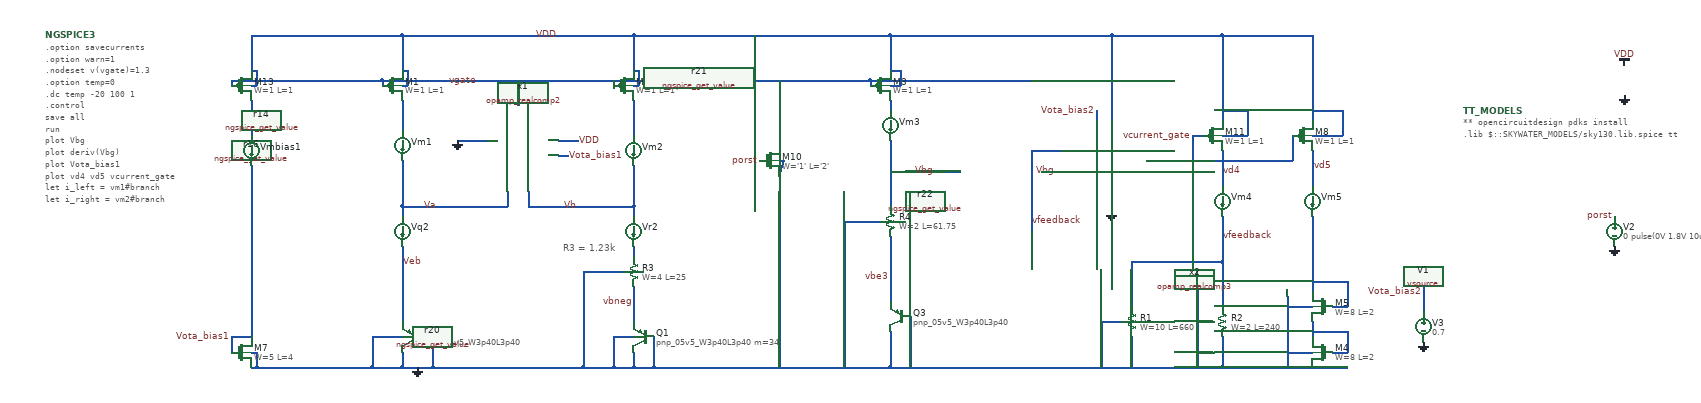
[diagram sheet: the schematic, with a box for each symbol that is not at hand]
v {xschem version=3.0.0 file_version=1.2 }
G {}
K {}
V {}
S {}
E {}
T {R3 = 1.23k} -650 -260 0 0 0.4 0.4 {}
N -970 -40 -970 -10 { lab=GND}
N -1030 -70 -970 -70 { lab=GND}
N -1030 -70 -1030 -10 { lab=GND}
N -970 -670 -750 -670 { lab=VDD}
N -510 -670 -310 -670 { lab=VDD}
N -510 -330 -510 -310 { lab=Vb}
N -510 -410 -510 -330 { lab=Vb}
N 0 -460 0 -330 { lab=Vbg}
N -510 -250 -510 -230 { lab=#net1}
N -510 -540 -510 -470 { lab=#net2}
N -510 -170 -510 -100 { lab=vbneg}
N -470 -70 -470 -10 { lab=GND}
N -510 -40 -510 -10 { lab=GND}
N -550 -70 -510 -70 { lab=GND}
N -550 -70 -550 -10 { lab=GND}
N -930 -70 -910 -70 { lab=GND}
N -910 -70 -910 -10 { lab=GND}
N -610 -200 -530 -200 { lab=GND}
N -610 -200 -610 -10 { lab=GND}
N -970 -250 -970 -100 { lab=Veb}
N -620 -330 -510 -330 { lab=Vb}
N -1270 -40 -1260 -40 { lab=GND}
N -1310 -70 -1310 -40 { lab=Vota_bias1}
N -1310 -70 -1270 -70 { lab=Vota_bias1}
N -1260 -40 -1260 -10 { lab=GND}
N -120 -670 0 -670 { lab=VDD}
N -510 -670 -510 -600 { lab=VDD}
N -120 -10 0 -10 { lab=GND}
N -970 -330 -970 -310 { lab=Va}
N -550 -580 -550 -570 { lab=vgate}
N -1010 -580 -1010 -570 { lab=vgate}
N -970 -540 -970 -480 { lab=#net3}
N -1270 -570 -1260 -570 { lab=VDD}
N -1260 -600 -1260 -570 { lab=VDD}
N -1270 -600 -1260 -600 { lab=VDD}
N -970 -570 -960 -570 { lab=VDD}
N -960 -600 -960 -570 { lab=VDD}
N -970 -600 -960 -600 { lab=VDD}
N -970 -670 -970 -600 { lab=VDD}
N -510 -570 -500 -570 { lab=VDD}
N -500 -600 -500 -570 { lab=VDD}
N -510 -600 -500 -600 { lab=VDD}
N -1230 -670 -970 -670 { lab=VDD}
N -70 -580 -40 -580 { lab=vgate}
N -1310 -580 -1310 -570 { lab=vgate}
N -1270 -670 -1270 -600 { lab=VDD}
N -1270 -350 -1270 -70 { lab=Vota_bias1}
N -970 -330 -900 -330 { lab=Va}
N -1030 -10 -970 -10 { lab=GND}
N -1100 -10 -1030 -10 { lab=GND}
N -1220 -10 -1100 -10 { lab=GND}
N -470 -10 -380 -10 { lab=GND}
N -510 -10 -470 -10 { lab=GND}
N -550 -10 -510 -10 { lab=GND}
N -610 -10 -550 -10 { lab=GND}
N -970 -10 -910 -10 { lab=GND}
N -910 -10 -850 -10 { lab=GND}
N 0 -270 0 -250 { lab=vbe3}
N -310 -670 -120 -670 { lab=VDD}
N -1010 -580 -790 -580 { lab=vgate}
N -790 -580 -310 -580 { lab=vgate}
N -970 -420 -970 -330 { lab=Va}
N -1270 -670 -1230 -670 { lab=VDD}
N -1260 -10 -1220 -10 { lab=GND}
N -1170 -580 -1010 -580 { lab=vgate}
N -1310 -580 -1170 -580 { lab=vgate}
N -270 -670 -270 -650 { lab=VDD}
N -270 -590 -270 -580 { lab=vgate}
N 0 -670 300 -670 {
lab=VDD}
N -720 -330 -620 -330 {
lab=Vb}
N -720 -360 -720 -330 {
lab=Vb}
N -900 -330 -760 -330 {
lab=Va}
N -760 -360 -760 -330 {
lab=Va}
N -740 -580 -740 -530 {
lab=vgate}
N -750 -670 -510 -670 {
lab=VDD}
N -310 -580 -70 -580 {
lab=vgate}
N -850 -10 -610 -10 {
lab=GND}
N -380 -10 -120 -10 {
lab=GND}
N -860 -460 -800 -460 {
lab=GND}
N -660 -460 -620 -460 {
lab=VDD}
N -660 -430 -640 -430 {
lab=Vota_bias1}
N 0 -250 0 -140 {
lab=vbe3}
N 0 -80 0 -10 {
lab=GND}
N 40 -110 40 -10 {
lab=GND}
N 0 -400 140 -400 {
lab=Vbg}
N -1270 -540 -1270 -470 {
lab=#net4}
N -1270 -410 -1270 -350 {
lab=Vota_bias1}
N -90 -300 -20 -300 {
lab=GND}
N -90 -300 -90 -10 {
lab=GND}
N -40 -580 280 -580 {
lab=vgate}
N -40 -580 -40 -570 {
lab=vgate}
N 0 -670 0 -600 {
lab=VDD}
N 0 -540 0 -520 {
lab=#net5}
N -1270 -10 -1260 -10 {
lab=GND}
N -0 -570 20 -570 {
lab=VDD}
N 20 -600 20 -570 {
lab=VDD}
N 0 -600 20 -600 {
lab=VDD}
N -220 -390 -220 -10 {
lab=GND}
N -220 -420 -210 -420 { lab=GND}
N -220 -390 -210 -420 { lab=GND}
N 410 -670 440 -670 {
lab=VDD}
N 440 -670 440 -500 {
lab=VDD}
N 280 -440 340 -440 {
lab=vfeedback}
N 560 -420 620 -420 {
lab=vcurrent_gate}
N 440 -670 660 -670 {
lab=VDD}
N 440 -360 440 -320 {
lab=GND}
N 660 -390 660 -370 {
lab=vd4}
N 660 -310 660 -280 {
lab=vfeedback}
N 660 -440 660 -390 {
lab=vd4}
N 600 -470 600 -420 {
lab=vcurrent_gate}
N 600 -470 620 -470 {
lab=vcurrent_gate}
N 660 -670 660 -500 {
lab=VDD}
N 840 -390 840 -370 {
lab=vd5}
N 840 -440 840 -390 {
lab=vd5}
N 620 -420 780 -420 {
lab=vcurrent_gate}
N 840 -670 840 -500 {
lab=VDD}
N 660 -670 840 -670 {
lab=VDD}
N 790 -150 790 -10 {
lab=GND}
N 660 -470 710 -470 {
lab=VDD}
N 710 -520 710 -470 {
lab=VDD}
N 660 -520 710 -520 {
lab=VDD}
N 840 -470 900 -470 {
lab=VDD}
N 900 -520 900 -470 {
lab=VDD}
N 840 -520 900 -520 {
lab=VDD}
N 300 -400 340 -400 {
lab=Vbg}
N 300 -670 410 -670 {
lab=VDD}
N 370 -10 660 -10 {
lab=GND}
N 840 -10 910 -10 {
lab=GND}
N 410 -520 410 -500 {
lab=Vota_bias2}
N 660 -280 660 -250 {
lab=vfeedback}
N 480 -220 660 -220 {
lab=vfeedback}
N 480 -220 480 -130 {
lab=vfeedback}
N 480 -70 480 -20 {
lab=GND}
N 420 -100 460 -100 {
lab=GND}
N 420 -100 420 -20 {
lab=GND}
N 660 -250 660 -220 {
lab=vfeedback}
N 420 -20 420 -10 {
lab=GND}
N 480 -20 480 -10 {
lab=GND}
N 610 -20 610 -10 {
lab=GND}
N 840 -100 840 -70 {
lab=#net6}
N 840 -200 840 -160 {
lab=#net7}
N 840 -310 840 -260 {
lab=#net7}
N 880 -40 910 -40 {
lab=#net6}
N 910 -80 910 -40 {
lab=#net6}
N 910 -180 910 -130 {
lab=#net7}
N 840 -180 910 -180 {
lab=#net7}
N 790 -130 840 -130 {
lab=GND}
N 790 -40 840 -40 {
lab=GND}
N 880 -130 910 -130 {
lab=#net7}
N 840 -260 840 -200 {
lab=#net7}
N 840 -80 910 -80 {
lab=#net6}
N 660 -10 790 -10 {
lab=GND}
N 790 -10 840 -10 {
lab=GND}
N 610 -190 640 -190 {
lab=GND}
N 610 -190 610 -90 {
lab=GND}
N 660 -220 660 -160 {
lab=vfeedback}
N 610 -40 640 -40 {
lab=GND}
N 610 -100 640 -100 {
lab=GND}
N 660 -70 660 -10 {
lab=GND}
N 610 -90 610 -20 {
lab=GND}
N 660 -160 660 -130 {
lab=vfeedback}
N 0 -10 370 -10 {
lab=GND}
N 1060 -170 1060 -120 {
lab=Vota_bias2}
N -220 -500 -220 -450 {
lab=vgate}
N -220 -580 -220 -500 {
lab=vgate}
N 280 -310 280 -280 {
lab=vfeedback}
N 280 -400 280 -310 {
lab=vfeedback}
N 280 -440 280 -400 {
lab=vfeedback}
N 510 -420 560 -420 {
lab=vcurrent_gate}
N 780 -420 800 -420 {
lab=vcurrent_gate}
N 800 -470 800 -420 {
lab=vcurrent_gate}
C {devices/code.sym} 1140 -520 0 0 {name=TT_MODELS
only_toplevel=true
format="tcleval( @value )"
value="
** opencircuitdesign pdks install
.lib $::SKYWATER_MODELS/sky130.lib.spice tt

"
spice_ignore=false}
C {sky130_fd_pr/pnp_05v5.sym} -950 -70 0 1 {name=Q2
model=pnp_05v5_W3p40L3p40
spiceprefix=X
}
C {devices/gnd.sym} -940 -10 0 0 {name=l1 lab=GND}
C {devices/lab_pin.sym} -900 -330 3 0 {name=l5 lab=Va}
C {devices/lab_pin.sym} -620 -330 3 0 {name=l6 lab=Vb}
C {devices/ammeter.sym} -510 -280 0 0 {name=Vr2 current=4.3334e-06}
C {devices/ammeter.sym} -970 -450 0 0 {name=Vm1 current=1.0057e-05}
C {devices/ammeter.sym} -510 -440 0 0 {name=Vm2 current=1.0057e-05}
C {devices/ammeter.sym} 0 -490 0 0 {name=Vm3 current=1.0239e-05}
C {devices/ammeter.sym} -970 -280 0 0 {name=Vq2 current=4.3346e-06}
C {sky130_fd_pr/pnp_05v5.sym} -490 -70 0 1 {name=Q1
model="pnp_05v5_W3p40L3p40 m=34"
spiceprefix=X
}
C {devices/lab_pin.sym} -510 -140 0 0 {name=l4 lab=vbneg}
C {devices/lab_pin.sym} -970 -220 2 0 {name=l10 lab=Veb}
C {devices/lab_wire.sym} -820 -580 0 0 {name=l11 lab=vgate}
C {sky130_fd_pr/nfet_01v8_lvt.sym} -1290 -40 0 0 {name=M7
L=4
W=5
nf=1
mult=1
ad="'int((nf+1)/2) * W/nf * 0.29'" 
pd="'2*int((nf+1)/2) * (W/nf + 0.29)'"
as="'int((nf+2)/2) * W/nf * 0.29'" 
ps="'2*int((nf+2)/2) * (W/nf + 0.29)'"
nrd="'0.29 / W'" nrs="'0.29 / W'"
sa=0 sb=0 sd=0
model=nfet_01v8_lvt
spiceprefix=X
}
C {sky130_fd_pr/pfet_01v8_lvt.sym} -1290 -570 0 0 {name=M13
L=1
W=1
nf=1
mult=10
ad="'int((nf+1)/2) * W/nf * 0.29'" 
pd="'2*int((nf+1)/2) * (W/nf + 0.29)'"
as="'int((nf+2)/2) * W/nf * 0.29'" 
ps="'2*int((nf+2)/2) * (W/nf + 0.29)'"
nrd="'0.29 / W'" nrs="'0.29 / W'"
sa=0 sb=0 sd=0
model=pfet_01v8_lvt
spiceprefix=X
}
C {sky130_fd_pr/pfet_01v8_lvt.sym} -990 -570 0 0 {name=M1
L=1
W=1
nf=1
mult=28
ad="'int((nf+1)/2) * W/nf * 0.29'" 
pd="'2*int((nf+1)/2) * (W/nf + 0.29)'"
as="'int((nf+2)/2) * W/nf * 0.29'" 
ps="'2*int((nf+2)/2) * (W/nf + 0.29)'"
nrd="'0.29 / W'" nrs="'0.29 / W'"
sa=0 sb=0 sd=0
model=pfet_01v8_lvt
spiceprefix=X
}
C {sky130_fd_pr/pfet_01v8_lvt.sym} -530 -570 0 0 {name=M2
L=1
W=1
nf=1
mult=28
ad="'int((nf+1)/2) * W/nf * 0.29'" 
pd="'2*int((nf+1)/2) * (W/nf + 0.29)'"
as="'int((nf+2)/2) * W/nf * 0.29'" 
ps="'2*int((nf+2)/2) * (W/nf + 0.29)'"
nrd="'0.29 / W'" nrs="'0.29 / W'"
sa=0 sb=0 sd=0
model=pfet_01v8_lvt
spiceprefix=X
}
C {sky130_fd_pr/pfet_01v8_lvt.sym} -20 -570 0 0 {name=M3
L=1
W=1
nf=1
mult=28
ad="'int((nf+1)/2) * W/nf * 0.29'" 
pd="'2*int((nf+1)/2) * (W/nf + 0.29)'"
as="'int((nf+2)/2) * W/nf * 0.29'" 
ps="'2*int((nf+2)/2) * (W/nf + 0.29)'"
nrd="'0.29 / W'" nrs="'0.29 / W'"
sa=0 sb=0 sd=0
model=pfet_01v8_lvt
spiceprefix=X
}
C {devices/ngspice_probe.sym} -970 -330 0 0 {name=r1}
C {devices/ngspice_probe.sym} -510 -330 0 0 {name=r2}
C {devices/ngspice_probe.sym} -1270 -320 0 0 {name=r3}
C {devices/ngspice_probe.sym} -820 -580 0 0 {name=r5}
C {devices/ngspice_probe.sym} -510 -140 0 0 {name=r9}
C {devices/ngspice_get_value.sym} -1270 -440 0 0 {name=r16 node=i(@m.xm13.msky130_fd_pr__pfet_01v8_lvt[id])
descr="I="}
C {devices/ngspice_get_value.sym} -1250 -500 0 0 {name=r14 node=@m.xm13.msky130_fd_pr__pfet_01v8_lvt[gm]
descr="gm="}
C {devices/ngspice_get_value.sym} -950 -500 0 0 {name=r20 node=@m.xm1.msky130_fd_pr__pfet_01v8_lvt[gm]
descr="gm="}
C {devices/ngspice_get_value.sym} -540 -500 0 1 {name=r21 node=@m.xm2.msky130_fd_pr__pfet_01v8_lvt[gm]
descr="gm="}
C {devices/ngspice_get_value.sym} 10 -530 0 0 {name=r22 node=@m.xm3.msky130_fd_pr__pfet_01v8_lvt[gm]
descr="gm="}
C {devices/gnd.sym} -860 -460 0 0 {name=l3 lab=GND}
C {devices/lab_wire.sym} -620 -460 0 1 {name=l14 lab=VDD}
C {devices/lab_pin.sym} 0 -190 0 0 {name=l15 lab=vbe3}
C {sky130_fd_pr/pnp_05v5.sym} 20 -110 0 1 {name=Q3
model=pnp_05v5_W3p40L3p40
*model="pnp_05v5_W3p40L3p40 m=1"
spiceprefix=X
}
C {lab_wire.sym} 90 -400 0 0 {name=l8 sig_type=std_logic lab=Vbg}
C {lab_wire.sym} -660 -670 0 0 {name=l16 sig_type=std_logic lab=VDD}
C {devices/lab_pin.sym} -1310 -70 2 1 {name=l2 lab=Vota_bias1}
C {devices/lab_pin.sym} -640 -430 2 0 {name=l18 lab=Vota_bias1}
C {devices/ammeter.sym} -1270 -440 0 0 {name=Vmbias1 current=1.0057e-05}
C {sky130_fd_pr/res_high_po.sym} -510 -200 0 0 {name=R3
W=4
L=25
model=res_high_po
spiceprefix=X
mult=1}
C {sky130_fd_pr/res_high_po.sym} 0 -300 0 0 {name=R4
W=2
L=61.75
model=res_high_po
spiceprefix=X
mult=1}
C {devices/vsource.sym} 1460 -580 0 0 {name=V1 net_name=true 
*value="'VDD' pwl 0us 0 1us 'VDD'"
value=1.8}
C {devices/vdd.sym} 1460 -610 0 0 {name=l9 lab=VDD}
C {devices/gnd.sym} 1460 -550 0 0 {name=l22 lab=GND}
C {devices/vsource.sym} 1440 -280 0 0 {name=V2 net_name=true value="0 pulse(0V 1.8V 10us 0us 0us 5us)"}
C {devices/gnd.sym} 1440 -250 0 0 {name=l12 lab=GND}
C {devices/lab_pin.sym} 1440 -310 0 0 {name=l23 lab=porst}
C {design/opamp/opamp_realcomp2.sym} -740 -460 1 1 {name=x1}
C {sky130_fd_pr/nfet_01v8_lvt.sym} -240 -420 0 0 {name=M10
L='2'
W='1'
nf=1
mult=34
ad="'int((nf+1)/2) * W/nf * 0.29'" 
pd="'2*int((nf+1)/2) * (W/nf + 0.29)'"
as="'int((nf+2)/2) * W/nf * 0.29'" 
ps="'2*int((nf+2)/2) * (W/nf + 0.29)'"
nrd="'0.29 / W'" nrs="'0.29 / W'"
sa=0 sb=0 sd=0
model=nfet_01v8_lvt
spiceprefix=X
}
C {devices/lab_pin.sym} -260 -420 0 0 {name=l26 lab=porst}
C {sky130_fd_pr/pfet_01v8_lvt.sym} 640 -470 0 0 {name=M11
L=1
W=1
nf=1
mult=5
ad="'int((nf+1)/2) * W/nf * 0.29'" 
pd="'2*int((nf+1)/2) * (W/nf + 0.29)'"
as="'int((nf+2)/2) * W/nf * 0.29'" 
ps="'2*int((nf+2)/2) * (W/nf + 0.29)'"
nrd="'0.29 / W'" nrs="'0.29 / W'"
sa=0 sb=0 sd=0
model=pfet_01v8_lvt
spiceprefix=X
}
C {devices/gnd.sym} 440 -320 0 0 {name=l13 lab=GND}
C {devices/ammeter.sym} 660 -340 0 0 {name=Vm4 current=1.0239e-05}
C {sky130_fd_pr/pfet_01v8_lvt.sym} 820 -470 0 0 {name=M8
L=1
W=1
nf=1
mult=5
ad="'int((nf+1)/2) * W/nf * 0.29'" 
pd="'2*int((nf+1)/2) * (W/nf + 0.29)'"
as="'int((nf+2)/2) * W/nf * 0.29'" 
ps="'2*int((nf+2)/2) * (W/nf + 0.29)'"
nrd="'0.29 / W'" nrs="'0.29 / W'"
sa=0 sb=0 sd=0
model=pfet_01v8_lvt
spiceprefix=X
}
C {devices/ammeter.sym} 840 -340 0 0 {name=Vm5 current=1.0239e-05}
C {sky130_fd_pr/nfet_01v8_lvt.sym} 860 -40 0 1 {name=M4
L=2
W=8
nf=1
mult=8
ad="'int((nf+1)/2) * W/nf * 0.29'" 
pd="'2*int((nf+1)/2) * (W/nf + 0.29)'"
as="'int((nf+2)/2) * W/nf * 0.29'" 
ps="'2*int((nf+2)/2) * (W/nf + 0.29)'"
nrd="'0.29 / W'" nrs="'0.29 / W'"
sa=0 sb=0 sd=0
model=nfet_01v8_lvt
spiceprefix=X
}
C {devices/lab_pin.sym} 840 -410 0 1 {name=l24 lab=vd5}
C {devices/lab_pin.sym} 660 -400 0 1 {name=l25 lab=vd4}
C {devices/lab_pin.sym} 410 -520 2 1 {name=l19 lab=Vota_bias2}
C {sky130_fd_pr/nfet_01v8_lvt.sym} 860 -130 0 1 {name=M5
L=2
W=8
nf=1
mult=8
ad="'int((nf+1)/2) * W/nf * 0.29'" 
pd="'2*int((nf+1)/2) * (W/nf + 0.29)'"
as="'int((nf+2)/2) * W/nf * 0.29'" 
ps="'2*int((nf+2)/2) * (W/nf + 0.29)'"
nrd="'0.29 / W'" nrs="'0.29 / W'"
sa=0 sb=0 sd=0
model=nfet_01v8_lvt
spiceprefix=X
}
C {devices/vsource.sym} 1060 -90 0 0 {name=V3 net_name=true 
*value="'VDD' pwl 0us 0 1us 'VDD'"
value=0.7}
C {devices/gnd.sym} 1060 -60 0 0 {name=l27 lab=GND}
C {devices/lab_pin.sym} 1060 -160 2 1 {name=l17 lab=Vota_bias2}
C {lab_wire.sym} 330 -400 0 0 {name=l7 sig_type=std_logic lab=Vbg}
C {devices/lab_pin.sym} 600 -470 0 0 {name=l21 lab=vcurrent_gate}
C {devices/lab_pin.sym} 660 -270 0 1 {name=l29 lab=vfeedback}
C {devices/lab_pin.sym} 280 -300 0 1 {name=l20 lab=vfeedback}
C {design/opamp/opamp_realcomp3.sym} 440 -420 0 0 {name=x2}
C {devices/code_shown.sym} -1680 -670 0 0 {name=NGSPICE3
only_toplevel=true
spice_ignore=false
value="
.option savecurrents
.option warn=1
.nodeset v(vgate)=1.3
.option temp=0
.dc temp -20 100 1
.control
save all

run
plot Vbg
plot deriv(Vbg)
plot Vota_bias1
plot vd4 vd5 vcurrent_gate

let i_left = vm1#branch
let i_right = vm2#branch
let i_3 = vm3#branch

let iout = vm3#branch
let iref = vm4#branch
let iref_final = vm5#branch

plot iref iref_final
plot deriv(iref) deriv(iref_final)

save vbg deriv(vbg)




unset askquit
*quit
.endc
" }
C {sky130_fd_pr/res_high_po.sym} 660 -100 0 0 {name=R2
W=2
L=240
model=res_high_po
spiceprefix=X
mult=1}
C {sky130_fd_pr/res_high_po.sym} 480 -100 0 0 {name=R1
W=10
L=660
model=res_xhigh_po
spiceprefix=X
mult=1}
